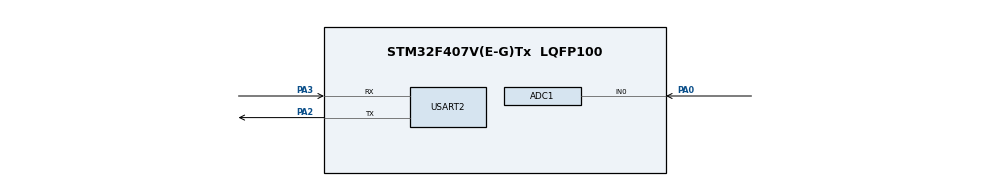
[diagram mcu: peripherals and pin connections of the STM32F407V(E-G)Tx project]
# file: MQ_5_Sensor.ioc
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ADC1.Channel-0\#ChannelRegularConversion=ADC_CHANNEL_0
ADC1.NbrOfConversionFlag=1
ADC1.Rank-0\#ChannelRegularConversion=1
ADC1.SamplingTime-0\#ChannelRegularConversion=ADC_SAMPLETIME_3CYCLES
ADC1.master=1
Mcu.Family=STM32F4
Mcu.Name=STM32F407V(E-G)Tx
Mcu.Package=LQFP100
NVIC.PriorityGroup=NVIC_PRIORITYGROUP_0
PA0-WKUP.Signal=ADCx_IN0
PA2.Mode=Asynchronous
PA2.Signal=USART2_TX
PA3.Mode=Asynchronous
PA3.Signal=USART2_RX
ProjectManager.HeapSize=0x200
ProjectManager.StackSize=0x400
ProjectManager.TargetToolchain=STM32CubeIDE
RCC.48MHZClocksFreq_Value=48000000
RCC.AHBFreq_Value=168000000
RCC.APB1CLKDivider=RCC_HCLK_DIV4
RCC.APB1Freq_Value=42000000
RCC.APB1TimFreq_Value=84000000
RCC.APB2CLKDivider=RCC_HCLK_DIV2
RCC.APB2Freq_Value=84000000
RCC.APB2TimFreq_Value=168000000
RCC.CortexFreq_Value=168000000
RCC.HCLKFreq_Value=168000000
RCC.HSE_VALUE=8000000
RCC.HSI_VALUE=16000000
RCC.LSE_VALUE=32768
RCC.PLLM=8
RCC.PLLN=336
RCC.PLLQ=7
RCC.PLLSourceVirtual=RCC_PLLSOURCE_HSE
RCC.SYSCLKFreq_VALUE=168000000
RCC.SYSCLKSource=RCC_SYSCLKSOURCE_PLLCLK
RCC.VCOOutputFreq_Value=336000000
SH.ADCx_IN0.0=ADC1_IN0,IN0
USART2.VirtualMode=VM_ASYNC
board=STM32F407G-DISC1

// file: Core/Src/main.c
/* USER CODE BEGIN Header */

/**

  ******************************************************************************

  * @file           : main.c

  * @brief          : Main program body

  ******************************************************************************

  * @attention

  *

  * Copyright (c) 2023 STMicroelectronics.

  * All rights reserved.

  *

  * This software is licensed under terms that can be found in the LICENSE file

  * in the root directory of this software component.

  * If no LICENSE file comes with this software, it is provided AS-IS.

  *

  ******************************************************************************

  */

/* USER CODE END Header */
#include "main.h"

/* USER CODE BEGIN Includes */

#include <stdio.h>

/* USER CODE END Includes */

ADC_HandleTypeDef hadc1;

UART_HandleTypeDef huart2;

void SystemClock_Config(void);
static void MX_GPIO_Init(void);
static void MX_ADC1_Init(void);
static void MX_USART2_UART_Init(void);

int main(void)
{
  /* USER CODE BEGIN 1 */

	uint32_t value;

  /* USER CODE END 1 */

  /* MCU Configuration--------------------------------------------------------*/

  /* Reset of all peripherals, Initializes the Flash interface and the Systick. */
  HAL_Init();

  /* Configure the system clock */
  SystemClock_Config();

  /* Initialize all configured peripherals */
  MX_GPIO_Init();
  MX_ADC1_Init();
  MX_USART2_UART_Init();
  /* USER CODE BEGIN 2 */

  int count;

  /* USER CODE END 2 */

  /* Infinite loop */
  while (1)
  {

    /* USER CODE BEGIN 3 */

	 HAL_ADC_Start(&hadc1);
	 HAL_ADC_PollForConversion(&hadc1, HAL_MAX_DELAY);
	 value=HAL_ADC_GetValue(&hadc1);
	 char buffer[1000];
	 count = sprintf(buffer,"MQ-5: %d,\r\n",value);
	 HAL_UART_Transmit(&huart2,(uint8_t*)buffer, count, HAL_MAX_DELAY );
	 HAL_ADC_Stop(&hadc1);
	 HAL_Delay(2000);

  }

  /* USER CODE END 3 */
}

void SystemClock_Config(void)
{
  RCC_OscInitTypeDef RCC_OscInitStruct = {0};
  RCC_ClkInitTypeDef RCC_ClkInitStruct = {0};

  /** Configure the main internal regulator output voltage
  */
  __HAL_RCC_PWR_CLK_ENABLE();
  __HAL_PWR_VOLTAGESCALING_CONFIG(PWR_REGULATOR_VOLTAGE_SCALE1);

  /** Initializes the RCC Oscillators according to the specified parameters
  * in the RCC_OscInitTypeDef structure.
  */
  RCC_OscInitStruct.OscillatorType = RCC_OSCILLATORTYPE_HSI;
  RCC_OscInitStruct.HSIState = RCC_HSI_ON;
  RCC_OscInitStruct.HSICalibrationValue = RCC_HSICALIBRATION_DEFAULT;
  RCC_OscInitStruct.PLL.PLLState = RCC_PLL_NONE;
  if (HAL_RCC_OscConfig(&RCC_OscInitStruct) != HAL_OK)
  {
    Error_Handler();
  }

  /** Initializes the CPU, AHB and APB buses clocks
  */
  RCC_ClkInitStruct.ClockType = RCC_CLOCKTYPE_HCLK|RCC_CLOCKTYPE_SYSCLK
                              |RCC_CLOCKTYPE_PCLK1|RCC_CLOCKTYPE_PCLK2;
  RCC_ClkInitStruct.SYSCLKSource = RCC_SYSCLKSOURCE_HSI;
  RCC_ClkInitStruct.AHBCLKDivider = RCC_SYSCLK_DIV1;
  RCC_ClkInitStruct.APB1CLKDivider = RCC_HCLK_DIV1;
  RCC_ClkInitStruct.APB2CLKDivider = RCC_HCLK_DIV1;

  if (HAL_RCC_ClockConfig(&RCC_ClkInitStruct, FLASH_LATENCY_0) != HAL_OK)
  {
    Error_Handler();
  }
}

static void MX_ADC1_Init(void)
{

  ADC_ChannelConfTypeDef sConfig = {0};

  /** Configure the global features of the ADC (Clock, Resolution, Data Alignment and number of conversion)
  */
  hadc1.Instance = ADC1;
  hadc1.Init.ClockPrescaler = ADC_CLOCK_SYNC_PCLK_DIV2;
  hadc1.Init.Resolution = ADC_RESOLUTION_12B;
  hadc1.Init.ScanConvMode = DISABLE;
  hadc1.Init.ContinuousConvMode = DISABLE;
  hadc1.Init.DiscontinuousConvMode = DISABLE;
  hadc1.Init.ExternalTrigConvEdge = ADC_EXTERNALTRIGCONVEDGE_NONE;
  hadc1.Init.ExternalTrigConv = ADC_SOFTWARE_START;
  hadc1.Init.DataAlign = ADC_DATAALIGN_RIGHT;
  hadc1.Init.NbrOfConversion = 1;
  hadc1.Init.DMAContinuousRequests = DISABLE;
  hadc1.Init.EOCSelection = ADC_EOC_SINGLE_CONV;
  if (HAL_ADC_Init(&hadc1) != HAL_OK)
  {
    Error_Handler();
  }

  /** Configure for the selected ADC regular channel its corresponding rank in the sequencer and its sample time.
  */
  sConfig.Channel = ADC_CHANNEL_0;
  sConfig.Rank = 1;
  sConfig.SamplingTime = ADC_SAMPLETIME_3CYCLES;
  if (HAL_ADC_ConfigChannel(&hadc1, &sConfig) != HAL_OK)
  {
    Error_Handler();
  }

}

static void MX_USART2_UART_Init(void)
{

  huart2.Instance = USART2;
  huart2.Init.BaudRate = 115200;
  huart2.Init.WordLength = UART_WORDLENGTH_8B;
  huart2.Init.StopBits = UART_STOPBITS_1;
  huart2.Init.Parity = UART_PARITY_NONE;
  huart2.Init.Mode = UART_MODE_TX_RX;
  huart2.Init.HwFlowCtl = UART_HWCONTROL_NONE;
  huart2.Init.OverSampling = UART_OVERSAMPLING_16;
  if (HAL_UART_Init(&huart2) != HAL_OK)
  {
    Error_Handler();
  }

}

static void MX_GPIO_Init(void)
{

  /* GPIO Ports Clock Enable */
  __HAL_RCC_GPIOA_CLK_ENABLE();

}

void Error_Handler(void)
{
  __disable_irq();
  while (1)
  {
  }
}
